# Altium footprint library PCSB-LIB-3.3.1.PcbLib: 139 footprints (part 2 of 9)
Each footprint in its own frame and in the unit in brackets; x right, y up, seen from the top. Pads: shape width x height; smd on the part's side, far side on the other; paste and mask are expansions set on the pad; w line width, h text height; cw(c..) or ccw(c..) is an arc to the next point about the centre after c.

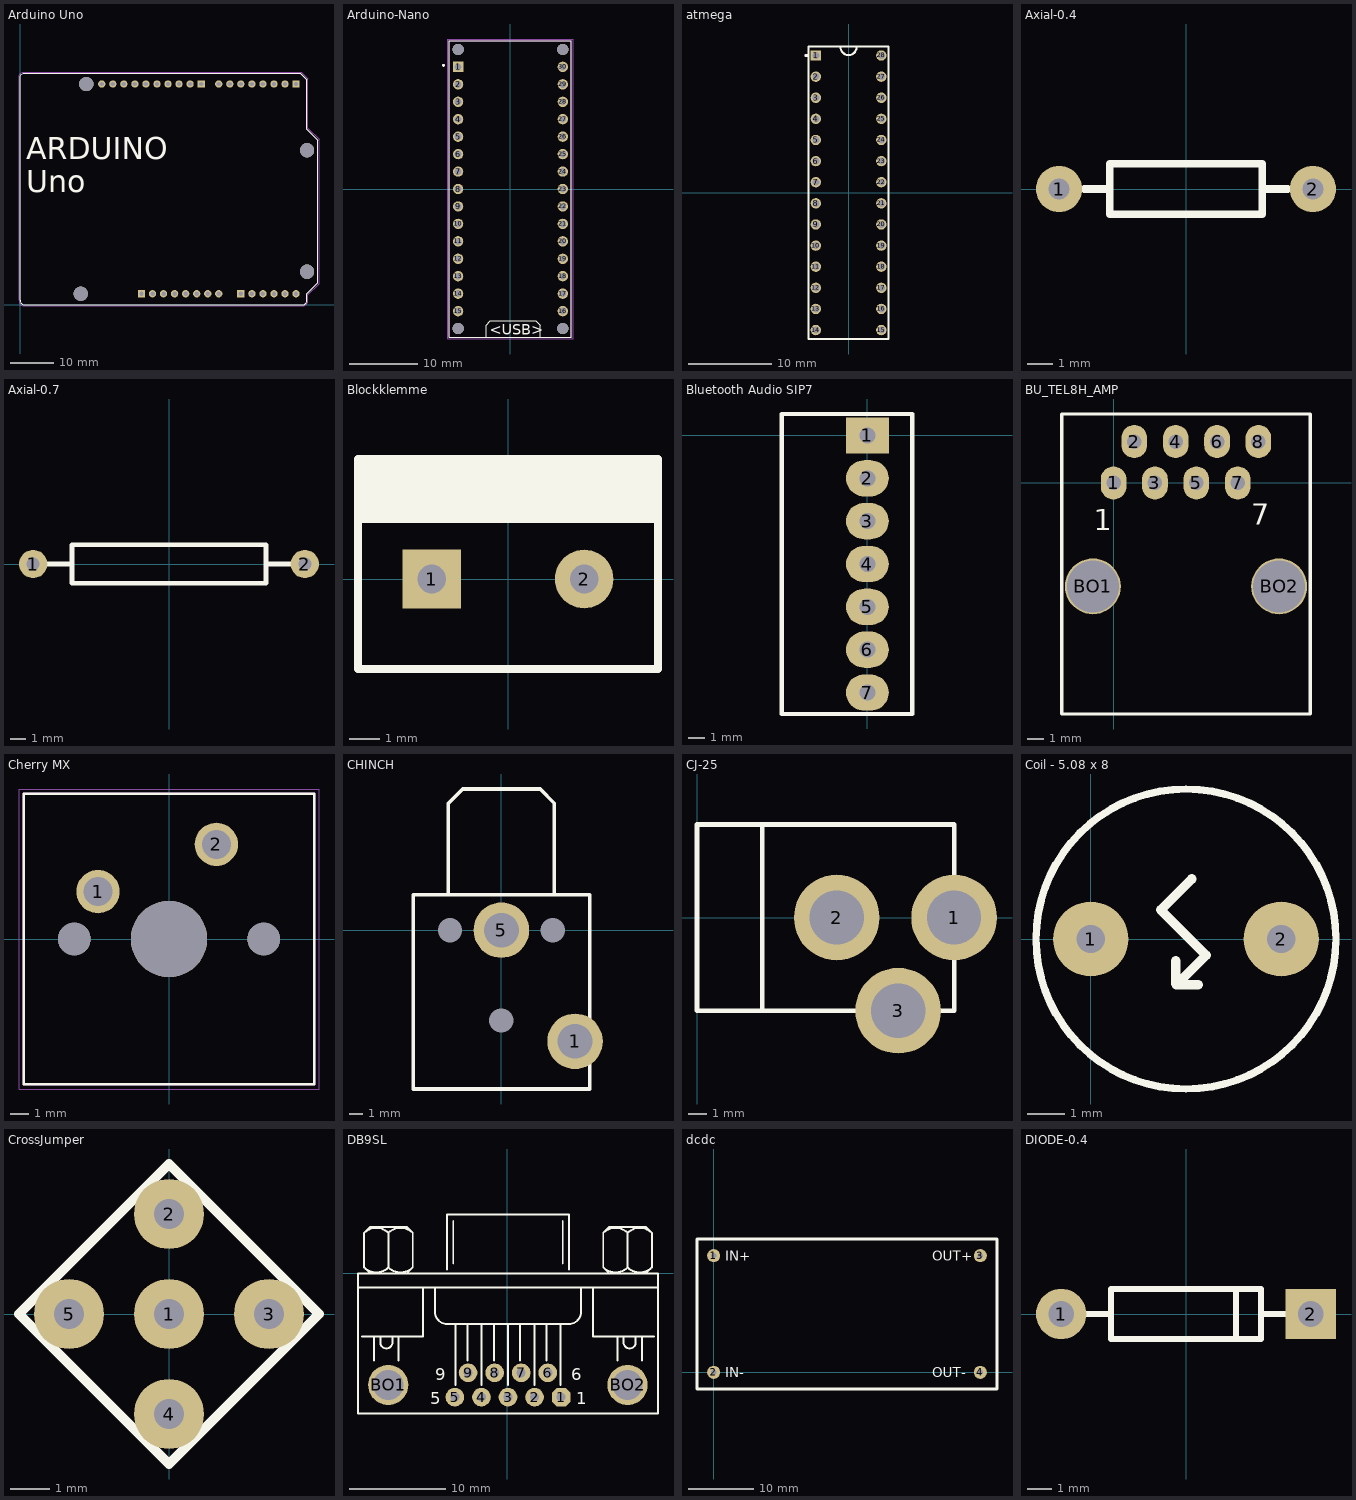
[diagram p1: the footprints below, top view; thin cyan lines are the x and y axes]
## Arduino Uno [mil]
pads (36):
  round 66 hole 40: 3V3(1400,100) 5V(1500,100) A1(2100,100) A2(2200,100) A3(2300,100) A4(2400,100) A4(SDA)(840,2000) A5(2500,100) A5(SCL)(740,2000) AREF(940,2000) D1(2400,2000) D2(2300,2000) D3(2200,2000) D4(2100,2000) D5(2000,2000) D6(1900,2000) D7(1800,2000) D9(1540,2000) D10(1440,2000) D11(1340,2000) D12(1240,2000) D13(1140,2000) GND_1(1700,100) GND_2(1600,100) GND_3(1040,2000) IOREF(1200,100) RST(1300,100) VIN(1800,100)
  rect 66x66 / inner round 66 / far side rect 66x66 hole 40: A0(2000,100) D0(2500,2000) D8(1640,2000) P1(1100,100)
  round 129.92 hole 129.92 unplated: ""(550,100) ""(600,2000) ""(2600,300) ""(2600,1400)
Top Overlay:
  lines w5: 0,39.1 1.67,29.1 5,19.94 11.66,11.61 19.99,4.94 29.16,1.61 39.15,-0.05 2559.09,-0.05 2569.09,1.61 2578.26,4.94 2586.59,11.61 2593.25,19.94 2596.58,29.1 2598.25,39.1 2598.25,99.91 2698.21,199.87 2698.21,1488.59 2598.25,1588.55 2598.25,2038.39 2538.27,2098.37 39.15,2098.37 29.16,2096.7 19.99,2092.54 11.66,2086.71 5,2078.38 1.67,2069.21 0,2058.39 0,39.1
  lines w10: 0,39.1 0,2058.39 1.67,2069.21 5,2078.38 11.66,2086.71 19.99,2092.54 29.16,2096.7 39.15,2098.37 2538.27,2098.37 2598.25,2038.39 2598.25,1588.55 2698.21,1488.59 2698.21,199.87 2598.25,99.91 2598.25,39.1 2596.58,29.1 2593.25,19.94 2586.59,11.61 2578.26,4.94 2569.09,1.61 2559.09,-0.05 39.15,-0.05 29.16,1.61 19.99,4.94 11.66,11.61 5,19.94 1.67,29.1 0,39.1
  text "ARDUINO  / Uno" at 55,1020.21 h200
Mechanical 15:
  lines w1.97: -9.84,39.1 -9.84,39.37 -9.84,2068.23 -8.18,2079.06 -4.84,2088.22 1.82,2096.55 10.15,2102.38 19.31,2106.55 29.31,2108.21 2548.11,2108.21 2608.09,2048.23 2608.09,1598.39 2708.06,1498.43 2708.06,190.03 2608.09,90.07 2608.09,39.1 ; -9.83,39.5 ccw(c36.7,36.25) 29.4,-9.82 ; 29.31,-9.9 2559.09,-9.9 ; 2558.61,-9.86 ccw(c2556.81,41.62) 2608.25,38.92

## Arduino-Nano [mm]
pads (34):
  rect 1.508x1.508 hole 1: 1(-7.62,17.78)
  round 1.508 hole 1: 2(-7.62,15.24) 3(-7.62,12.7) 4(-7.62,10.16) 5(-7.62,7.62) 6(-7.62,5.08) 7(-7.62,2.54) 8(-7.62,0) 9(-7.62,-2.54) 10(-7.62,-5.08) 11(-7.62,-7.62) 12(-7.62,-10.16) 13(-7.62,-12.7) 14(-7.62,-15.24) 15(-7.62,-17.78) 16(7.62,-17.78) 17(7.62,-15.24) 18(7.62,-12.7) 19(7.62,-10.16) 20(7.62,-7.62) 21(7.62,-5.08) 22(7.62,-2.54) 23(7.62,0) 24(7.62,2.54) 25(7.62,5.08) 26(7.62,7.62) 27(7.62,10.16) 28(7.62,12.7) 29(7.62,15.24) 30(7.62,17.78)
  round 1.651 hole 1.651 unplated: ""(-7.62,-20.32) ""(-7.62,20.32) ""(7.62,-20.32) ""(7.62,20.32)
Top Overlay:
  circle w0.2: c-9.75,18 r0.1
  lines w0.127: -3.556,-21.59 -3.556,-19.812 -2.921,-19.177 -2.159,-19.177 3.683,-19.177 4.318,-19.812 4.318,-21.59 ; -8.89,-21.59 8.89,-21.59 8.89,21.59 -8.89,21.59 -8.89,-21.59
  text "<USB>" at -3.048,-21.209 h1.52
Mechanical 13:
  circle w0.2: c-9.75,18 r0.1
  lines w0.127: -8.89,-21.59 -8.89,21.59 8.89,21.59 8.89,-21.59 -8.89,-21.59
Mechanical 15:
  lines w0.05: -9.14,-21.84 9.14,-21.84 9.14,21.84 -9.14,21.84 -9.14,-21.84

## atmega [mm]
pads (28):
  rect 1.25x1.25 hole 0.83: 1(-3.937,16.51)
  round 1.25 hole 0.83: 2(-3.937,13.97) 3(-3.937,11.43) 4(-3.937,8.89) 5(-3.937,6.35) 6(-3.937,3.81) 7(-3.937,1.27) 8(-3.937,-1.27) 9(-3.937,-3.81) 10(-3.937,-6.35) 11(-3.937,-8.89) 12(-3.937,-11.43) 13(-3.937,-13.97) 14(-3.937,-16.51) 15(3.937,-16.51) 16(3.937,-13.97) 17(3.937,-11.43) 18(3.937,-8.89) 19(3.937,-6.35) 20(3.937,-3.81) 21(3.937,-1.27) 22(3.937,1.27) 23(3.937,3.81) 24(3.937,6.35) 25(3.937,8.89) 26(3.937,11.43) 27(3.937,13.97) 28(3.937,16.51)
Top Overlay:
  circle w0.2: c-5.1,16.51 r0.1
  lines w0.254: -0.967,17.526 ccw(c0,17.526) 0.967,17.526 ; -4.812,-17.585 4.812,-17.585 4.812,17.585 -4.812,17.585 -4.812,-17.585
Mechanical 13:
  circle w0.2: c-5.1,16.51 r0.1

## Axial-0.4 [mm]
pads (2):
  round 1.85 hole 0.85: 1(-5.08,0) 2(5.08,0)
Top Overlay:
  lines w0.305: -4.064,0 -3.048,0 ; 3.048,0 4.064,0 ; -3.048,-1.016 3.048,-1.016 3.048,1.016 -3.048,1.016 -3.048,-1.016

## Axial-0.7 [mm]
pads (2):
  round 1.85 hole 0.85: 1(-8.89,0) 2(8.89,0)
Top Overlay:
  lines w0.305: -8.89,0 -6.35,0 ; 6.35,0 8.89,0 ; -6.35,-1.27 6.35,-1.27 6.35,1.27 -6.35,1.27 -6.35,-1.27

## Blockklemme [mm]
pads (2):
  rect 1.95x1.95 hole 0.95: 1(-2.54,0)
  round 1.95 hole 0.95: 2(2.54,0)
Top Overlay:
  rectangle: -5,2 5,4
  lines w0.254: -5,2 5,2 ; -5,-3 -5,3 -5,4 5,4 5,3 5,-3 -5,-3

## Bluetooth Audio SIP7 [mm]
pads (7):
  rect 2.54x2.15 / inner rect 2.54x1.27 / far side rect 2.54x2.15 hole 0.95: 1(0,0)
  oval 2.54x2.15 / inner oval 2.54x1.27 / far side oval 2.54x2.15 hole 0.95: 2(0,-2.54) 3(0,-5.08) 4(0,-7.62) 5(0,-10.16) 6(0,-12.7) 7(0,-15.24)
Top Overlay:
  lines w0.254: -5.08,-16.51 -5.08,1.27 2.667,1.27 2.667,-16.51 -5.08,-16.51

## BU_TEL8H_AMP [mil]
pads (10):
  oval 62x80 hole 35: 1(0,0) 2(50,100) 3(100,0) 4(150,100) 5(200,0) 6(250,100) 7(300,0) 8(350,100)
  round 135 hole 125: BO1(-50,-250) BO2(400,-250)
Bottom Layer:
  text "1" at -140,-15 h40
Top Overlay:
  lines w8: -125,-558.33 475,-558.33 475,166.67 -125,166.67 -125,-558.33
  text "7" at 332.45,-101.06 h50
  text "1" at -47.84,-114.13 h50

## Cherry MX [mil]
pads (5):
  round 91.5 hole 61: 1(-150,100) 2(100,200)
  round 69 hole 69 unplated: ""(-200,0) ""(200,0)
  round 161 hole 161 unplated: ""(0,0)
Top Overlay:
  lines w5: -307.09,-307.09 307.09,-307.09 307.09,307.09 -307.09,307.09 -307.09,-307.09
Mechanical 13:
  lines w5: -307.09,-307.09 -307.09,307.09 307.09,307.09 307.09,-307.09 -307.09,-307.09
Mechanical 15:
  lines w1.97: -316.93,-316.93 -316.93,316.93 316.93,316.93 316.93,-316.93 -316.93,-316.93

## CHINCH [mm] "RCA-Buchse bestellbar bei RS  Nr. 913-1021"
pads (5):
  round 4 / inner round 1.27 / far side round 4 hole 2.5: 1(5.3,-8) 5(0,0)
  round 0.5 hole 1.75: 2(3.7,0) 3(-3.7,0) 4(0,-6.5)
Top Overlay:
  lines w0.254: -3.81,2.54 -3.81,9.144 -2.794,10.16 2.794,10.16 3.81,9.144 3.81,2.54 ; -6.35,-11.43 6.35,-11.43 6.35,2.54 5.08,2.54 -5.08,2.54 -6.35,2.54 -6.35,-11.43

## CJ-25 [mm] "DC-Buchse 2.1mm Bestellbar bei RS Nr. 448-382"
height 1.7
pads (3):
  round 4.6 hole 2.9: 1(13.8,0) 2(7.5,0) 3(10.8,-5)
Top Overlay:
  lines w0.254: 3.5,-5 3.5,5 ; 0,-5 13.8,-5 13.8,5 0,5 0,-5

## Coil - 5.08 x 8 [mm]
pads (2):
  round 2 hole 0.75: 1(0,0) 2(5.08,0)
Top Overlay:
  circle w0.2: c2.54,0 r4
  lines w0.254: 2.261,-0.762 2.261,-1.194 ; 2.261,-0.584 2.261,-1.194 ; 2.692,1.6 1.867,0.775 3.073,-0.432 2.286,-1.219 ; 2.261,-1.194 2.286,-1.219 ; 2.286,-1.219 2.87,-1.219 ; 2.286,-1.219 2.87,-1.219 ; 2.286,-1.219 2.87,-1.219

## CrossJumper [mil]
pads (5):
  round 70 hole 30: 1(0,0) 2(0,100) 3(100,0) 4(0,-100) 5(-100,0)
Top Overlay:
  lines w10: -150,0 0,-150 150,0 0,150 -150,0

## DB9SL [mm]
pads (11):
  oct 1.95x1.95 hole 0.95: 1(5.6,-12.937)
  round 1.95 hole 0.95: 2(2.827,-12.937) 3(0.054,-12.937) 4(-2.718,-12.937) 5(-5.491,-12.937) 6(4.203,-10.397) 7(1.43,-10.397) 8(-1.343,-10.397) 9(-4.115,-10.397)
  round 4.2 hole 3.15: BO1(-12.455,-11.667) BO2(12.543,-11.667)
Top Overlay:
  lines w0.203: -15.609,-1.507 15.718,-1.507 ; -15.186,-6.587 -8.836,-6.587 -8.836,-1.507 ; -14.976,0.608 ccw(c-13.704,1.88) -12.432,0.608 ; -14.976,4.211 cw(c-13.704,2.938) -12.432,4.211 ; -14.339,-0.025 -14.974,0.61 -14.974,4.208 -14.339,4.843 -10.529,4.843 -9.894,4.208 -9.894,0.61 -10.529,-0.025 ; -13.916,-9.127 -13.916,-6.587 ; -13.281,-6.587 -13.281,-7.222 ccw(c-12.646,-7.222) -12.011,-7.222 -12.011,-6.587 ; -12.436,0.608 ccw(c-11.164,1.88) -9.892,0.608 ; -12.436,4.211 cw(c-11.164,2.938) -9.892,4.211 ; -12.434,0.61 -12.434,4.208 ; -11.376,-9.127 -11.376,-6.587 ; -7.566,-1.507 -7.566,-4.047 ccw(c-6.296,-4.047) -6.296,-5.317 6.404,-5.317 ccw(c6.404,-4.047) 7.674,-4.047 7.674,-1.507 ; -6.296,0.398 -6.296,6.113 6.404,6.113 6.404,0.398 ; -5.661,1.033 -5.661,5.478 ; -5.449,-11.667 -5.449,-5.317 ; -4.179,-9.127 -4.179,-5.317 ; -2.697,-11.667 -2.697,-5.317 ; -1.427,-9.127 -1.427,-5.317 ; 0.054,-11.667 0.054,-5.317 ; 1.324,-9.127 1.324,-5.317 ; 2.806,-11.667 2.806,-5.317 ; 4.076,-9.127 4.076,-8.915 4.076,-5.317 ; 5.558,-11.667 5.558,-5.317 ; 5.769,1.033 5.769,5.478 ; 8.944,-1.507 8.944,-6.587 15.294,-6.587 ; 10,0.608 ccw(c11.273,1.88) 12.545,0.608 ; 10,4.211 cw(c11.273,2.938) 12.545,4.211 ; 10.638,-0.025 10.003,0.61 10.003,4.208 10.638,4.843 14.448,4.843 15.083,4.208 15.083,0.61 14.448,-0.025 ; 11.484,-9.127 11.484,-6.587 ; 12.119,-6.587 12.119,-7.222 ccw(c12.754,-7.222) 13.389,-7.222 13.389,-6.587 ; 12.54,0.608 ccw(c13.813,1.88) 15.085,0.608 ; 12.54,4.211 cw(c13.813,2.938) 15.085,4.211 ; 12.543,0.61 12.543,4.208 ; 14.024,-9.127 14.024,-6.587 ; -15.609,-14.63 15.718,-14.63 15.718,-0.025 -15.609,-0.025 -15.609,-14.63
  text "6" at 6.658,-11.159 h1.27
  text "1" at 7.166,-13.699 h1.27
  text "5" at -8.074,-13.699 h1.27
  text "9" at -7.566,-11.159 h1.27

## dcdc [mm]
pads (4):
  round 2 hole 0.85: 1(0,17.78) 2(0,0) 3(40.64,17.78) 4(40.64,0)
Top Overlay:
  lines w0.4: -2.54,-2.54 -2.54,20.32 43.18,20.32 43.18,-2.54 -2.54,-2.54
  text "IN+" at 1.778,17.018 h1.52
  text "IN-" at 1.778,-0.762 h1.52
  text "OUT+" at 33.274,17.018 h1.52
  text "OUT-" at 33.274,-0.762 h1.52

## DIODE-0.4 [mm]
pads (2):
  round 2.05 hole 1.05: 1(-5.08,0)
  rect 2.05x2.05 hole 1.05: 2(5.08,0)
Top Overlay:
  lines w0.254: -4.064,0 -3.048,0 ; 2.032,-1.016 2.032,1.016 ; 3.048,0 4.064,0 ; -3.048,-1.016 3.048,-1.016 3.048,1.016 -3.048,1.016 -3.048,-1.016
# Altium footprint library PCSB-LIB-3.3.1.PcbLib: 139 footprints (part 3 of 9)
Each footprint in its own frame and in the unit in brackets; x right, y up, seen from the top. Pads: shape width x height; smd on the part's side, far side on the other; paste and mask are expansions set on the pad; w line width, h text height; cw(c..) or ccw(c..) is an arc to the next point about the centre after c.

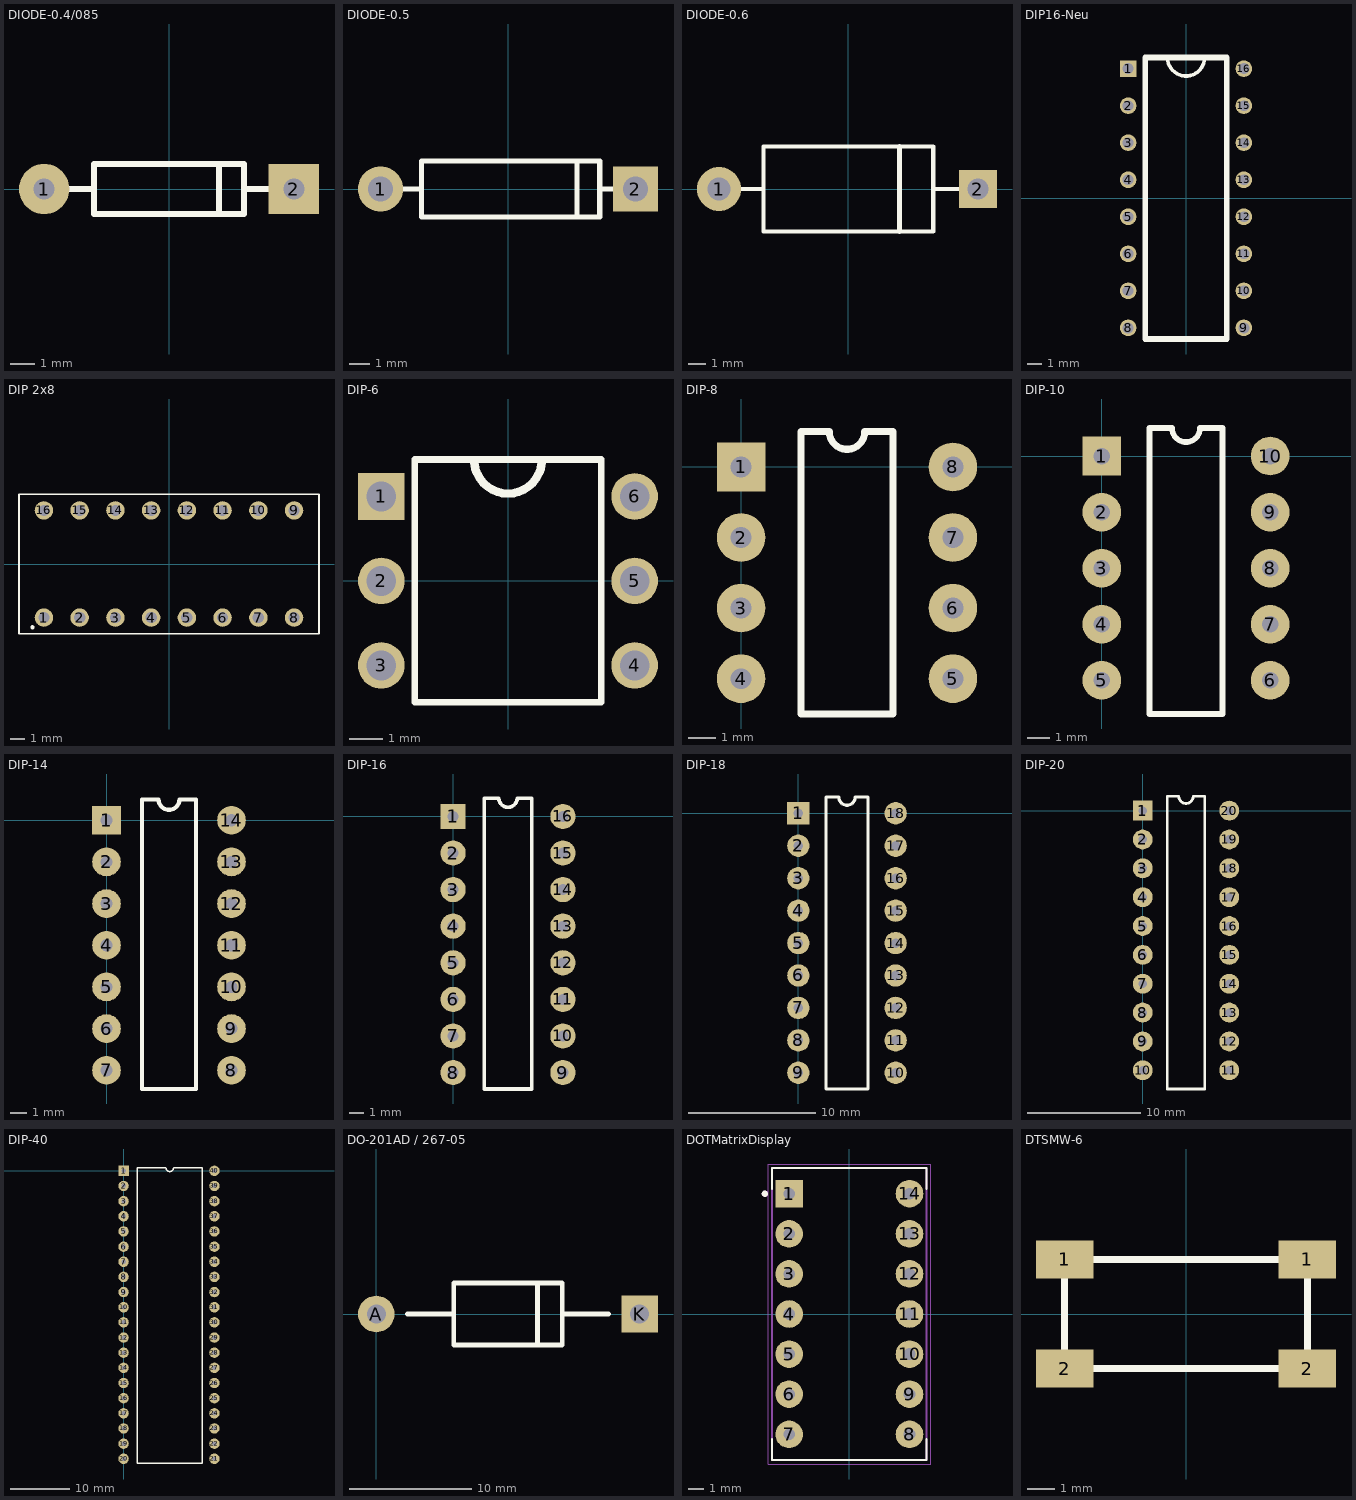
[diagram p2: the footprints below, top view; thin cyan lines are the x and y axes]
## DIODE-0.4/085 [mm]
pads (2):
  round 2.05 hole 0.85: 1(-5.08,0)
  rect 2.05x2.05 hole 0.85: 2(5.08,0)
Top Overlay:
  lines w0.254: -4.064,0 -3.048,0 ; 2.032,-1.016 2.032,1.016 ; 3.048,0 4.064,0 ; -3.048,-1.016 3.048,-1.016 3.048,1.016 -3.048,1.016 -3.048,-1.016

## DIODE-0.5 [mm]
pads (2):
  round 2.25 hole 1.25: 1(-6.35,0)
  rect 2.25x2.25 hole 1.25: 2(6.35,0)
Top Overlay:
  lines w0.254: -5.334,0 -4.318,0 ; 3.429,-1.397 3.429,1.397 ; 4.699,0 5.715,0 ; -4.318,-1.397 -4.318,1.397 4.572,1.397 4.572,-1.397 -4.318,-1.397

## DIODE-0.6 [mm]
pads (2):
  round 2.6 hole 1.35: 1(-7.62,0)
  rect 2.25x2.25 hole 1.25: 2(7.62,0)
Top Overlay:
  lines w0.254: -7,0 -5,0 ; -5,-2.5 -5,2.5 5,2.5 5,-2.5 -4.89,-2.5 ; 5,0 7.016,0
  lines w0.3: 3,-2.5 3,2.5

## DIP16-Neu [mm]
pads (16):
  rect 1.14x1.14 hole 0.74: 1(-3.97,8.89)
  round 1.14 hole 0.74: 2(-3.97,6.35) 3(-3.97,3.81) 4(-3.97,1.27) 5(-3.97,-1.27) 6(-3.97,-3.81) 7(-3.97,-6.35) 8(-3.97,-8.89) 9(3.97,-8.89) 10(3.97,-6.35) 11(3.97,-3.81) 12(3.97,-1.27) 13(3.97,1.27) 14(3.97,3.81) 15(3.97,6.35) 16(3.97,8.89)
Top Overlay:
  lines w0.254: -1.253,9.443 ccw(c0,9.653) 1.27,9.652
  lines w0.4: -2.794,-9.653 -2.794,9.653 2.794,9.653 2.794,-9.653 -2.794,-9.653

## DIP 2x8 [mm]
pads (16):
  round 1.308 hole 0.8: 1(-8.89,-3.81) 2(-6.35,-3.81) 3(-3.81,-3.81) 4(-1.27,-3.81) 5(1.27,-3.81) 6(3.81,-3.81) 7(6.35,-3.81) 8(8.89,-3.81) 9(8.89,3.81) 10(6.35,3.81) 11(3.81,3.81) 12(1.27,3.81) 13(-1.27,3.81) 14(-3.81,3.81) 15(-6.35,3.81) 16(-8.89,3.81)
Top Overlay:
  circle w0.2: c-9.7,-4.5 r0.05
  lines w0.127: -10.66,-4.95 -10.66,4.95 10.66,4.95 10.66,-4.95 -10.66,-4.95

## DIP-6 [mm]
pads (6):
  rect 1.4x1.4 hole 0.9: 1(-3.81,2.54)
  round 1.4 hole 0.9: 2(-3.81,0) 3(-3.81,-2.54) 4(3.81,-2.54) 5(3.81,0) 6(3.81,2.54)
Top Overlay:
  lines w0.2: -2.8,-3.65 2.8,-3.65 2.8,3.65 1.4,3.65 -1.4,3.65 -2.8,3.65 -2.8,-3.65
  lines w0.254: -1.016,3.556 ccw(c0,3.65) 1.016,3.556

## DIP-8 [mm]
pads (8):
  rect 1.75x1.75 hole 0.75: 1(0,0)
  round 1.75 hole 0.75: 2(0,-2.54) 3(0,-5.08) 4(0,-7.62) 5(7.62,-7.62) 6(7.62,-5.08) 7(7.62,-2.54) 8(7.62,0)
Top Overlay:
  lines w0.254: 2.159,-8.89 5.461,-8.89 5.461,1.27 4.445,1.27 cw(c3.81,1.27) 3.175,1.27 2.159,1.27 2.159,-8.89

## DIP-10 [mm]
pads (10):
  rect 1.75x1.75 hole 0.75: 1(0,0)
  round 1.75 hole 0.75: 2(0,-2.54) 3(0,-5.08) 4(0,-7.62) 5(0,-10.16) 6(7.62,-10.16) 7(7.62,-7.62) 8(7.62,-5.08) 9(7.62,-2.54) 10(7.62,0)
Top Overlay:
  lines w0.254: 2.159,-11.684 2.159,1.27 3.175,1.27 ccw(c3.81,1.27) 4.445,1.27 5.461,1.27 5.461,-11.684 2.159,-11.684

## DIP-14 [mm]
pads (14):
  rect 1.75x1.75 hole 0.75: 1(0,0)
  round 1.75 hole 0.75: 2(0,-2.54) 3(0,-5.08) 4(0,-7.62) 5(0,-10.16) 6(0,-12.7) 7(0,-15.24) 8(7.62,-15.24) 9(7.62,-12.7) 10(7.62,-10.16) 11(7.62,-7.62) 12(7.62,-5.08) 13(7.62,-2.54) 14(7.62,0)
Top Overlay:
  lines w0.254: 2.159,-16.383 2.159,1.27 3.175,1.27 ccw(c3.81,1.27) 4.445,1.27 5.461,1.27 5.461,-16.383 2.159,-16.383

## DIP-16 [mm]
pads (16):
  rect 1.75x1.75 hole 0.75: 1(0,0)
  round 1.75 hole 0.75: 2(0,-2.54) 3(0,-5.08) 4(0,-7.62) 5(0,-10.16) 6(0,-12.7) 7(0,-15.24) 8(0,-17.78) 9(7.62,-17.78) 10(7.62,-15.24) 11(7.62,-12.7) 12(7.62,-10.16) 13(7.62,-7.62) 14(7.62,-5.08) 15(7.62,-2.54) 16(7.62,0)
Top Overlay:
  lines w0.254: 2.159,-18.923 5.461,-18.923 5.461,1.27 4.445,1.27 cw(c3.81,1.27) 3.175,1.27 2.159,1.27 2.159,-18.923

## DIP-18 [mm]
pads (18):
  rect 1.75x1.75 hole 0.75: 1(0,0)
  round 1.75 hole 0.75: 2(0,-2.54) 3(0,-5.08) 4(0,-7.62) 5(0,-10.16) 6(0,-12.7) 7(0,-15.24) 8(0,-17.78) 9(0,-20.32) 10(7.62,-20.32) 11(7.62,-17.78) 12(7.62,-15.24) 13(7.62,-12.7) 14(7.62,-10.16) 15(7.62,-7.62) 16(7.62,-5.08) 17(7.62,-2.54) 18(7.62,0)
Top Overlay:
  lines w0.254: 2.159,-21.59 2.159,1.27 3.175,1.27 ccw(c3.81,1.27) 4.445,1.27 5.461,1.27 5.461,-21.59 2.159,-21.59

## DIP-20 [mm]
pads (20):
  rect 1.75x1.75 hole 0.75: 1(0,0)
  round 1.75 hole 0.75: 2(0,-2.54) 3(0,-5.08) 4(0,-7.62) 5(0,-10.16) 6(0,-12.7) 7(0,-15.24) 8(0,-17.78) 9(0,-20.32) 10(0,-22.86) 11(7.62,-22.86) 12(7.62,-20.32) 13(7.62,-17.78) 14(7.62,-15.24) 15(7.62,-12.7) 16(7.62,-10.16) 17(7.62,-7.62) 18(7.62,-5.08) 19(7.62,-2.54) 20(7.62,0)
Top Overlay:
  lines w0.254: 2.159,-24.511 2.159,1.27 3.175,1.27 ccw(c3.81,1.27) 4.445,1.27 5.461,1.27 5.461,-24.511 2.159,-24.511

## DIP-40 [mm]
pads (40):
  rect 1.75x1.75 hole 0.75: 1(0,0)
  round 1.75 hole 0.75: 2(0,-2.54) 3(0,-5.08) 4(0,-7.62) 5(0,-10.16) 6(0,-12.7) 7(0,-15.24) 8(0,-17.78) 9(0,-20.32) 10(0,-22.86) 11(0,-25.4) 12(0,-27.94) 13(0,-30.48) 14(0,-33.02) 15(0,-35.56) 16(0,-38.1) 17(0,-40.64) 18(0,-43.18) 19(0,-45.72) 20(0,-48.26) 21(15.24,-48.26) 22(15.24,-45.72) 23(15.24,-43.18) 24(15.24,-40.64) 25(15.24,-38.1) 26(15.24,-35.56) 27(15.24,-33.02) 28(15.24,-30.48) 29(15.24,-27.94) 30(15.24,-25.4) 31(15.24,-22.86) 32(15.24,-20.32) 33(15.24,-17.78) 34(15.24,-15.24) 35(15.24,-12.7) 36(15.24,-10.16) 37(15.24,-7.62) 38(15.24,-5.08) 39(15.24,-2.54) 40(15.24,0)
Top Overlay:
  lines w0.254: 2.286,-49.022 13.208,-49.022 13.208,0.508 8.382,0.508 cw(c7.747,0.508) 7.112,0.508 2.286,0.508 2.286,-49.022

## DO-201AD / 267-05 [mm]
height 5
pads (2):
  round 3 hole 1.55: A(0,0)
  rect 3x3 hole 1.55: K(21.59,0)
Top Overlay:
  lines w0.4: 2.54,0 6.35,0 ; 13.208,-2.54 13.208,2.54 ; 15.24,0 19.05,0 ; 6.35,-2.54 6.35,2.54 15.24,2.54 15.24,-2.54 6.35,-2.54

## DOTMatrixDisplay [mm]
pads (14):
  rect 1.75x1.75 hole 0.75: 1(-3.81,7.62)
  round 1.75 hole 0.75: 2(-3.81,5.08) 3(-3.81,2.54) 4(-3.81,0) 5(-3.81,-2.54) 6(-3.81,-5.08) 7(-3.81,-7.62) 8(3.81,-7.62) 9(3.81,-5.08) 10(3.81,-2.54) 11(3.81,0) 12(3.81,2.54) 13(3.81,5.08) 14(3.81,7.62)
Top Overlay:
  circle w0.2: c-5.35,7.62 r0.1
  lines w0.127: -4.9,-7.92 -4.9,-9.25 4.9,-9.25 4.9,-7.92 ; -4.9,7.92 -4.9,9.25 4.9,9.25 4.9,7.92
Mechanical 13:
  circle w0.2: c-5.35,7.62 r0.1
  lines w0.127: -4.9,-9.25 -4.9,9.25 4.9,9.25 4.9,-9.25 -4.9,-9.25
Mechanical 15:
  lines w0.05: -5.15,-9.5 5.15,-9.5 5.15,9.5 -5.15,9.5 -5.15,-9.5

## DTSMW-6 [mm]
height 17
pads (4):
  rect 2.1x1.4 smd: 1(-4.45,2) 1(4.45,2) 2(-4.45,-2) 2(4.45,-2)
Top Overlay:
  lines w0.254: -4.45,-2 -4.45,2 4.45,2 4.45,-2 -4.45,-2
3D body: height 17, standoff 0, extent -5.602,-2.802 5.602,2.802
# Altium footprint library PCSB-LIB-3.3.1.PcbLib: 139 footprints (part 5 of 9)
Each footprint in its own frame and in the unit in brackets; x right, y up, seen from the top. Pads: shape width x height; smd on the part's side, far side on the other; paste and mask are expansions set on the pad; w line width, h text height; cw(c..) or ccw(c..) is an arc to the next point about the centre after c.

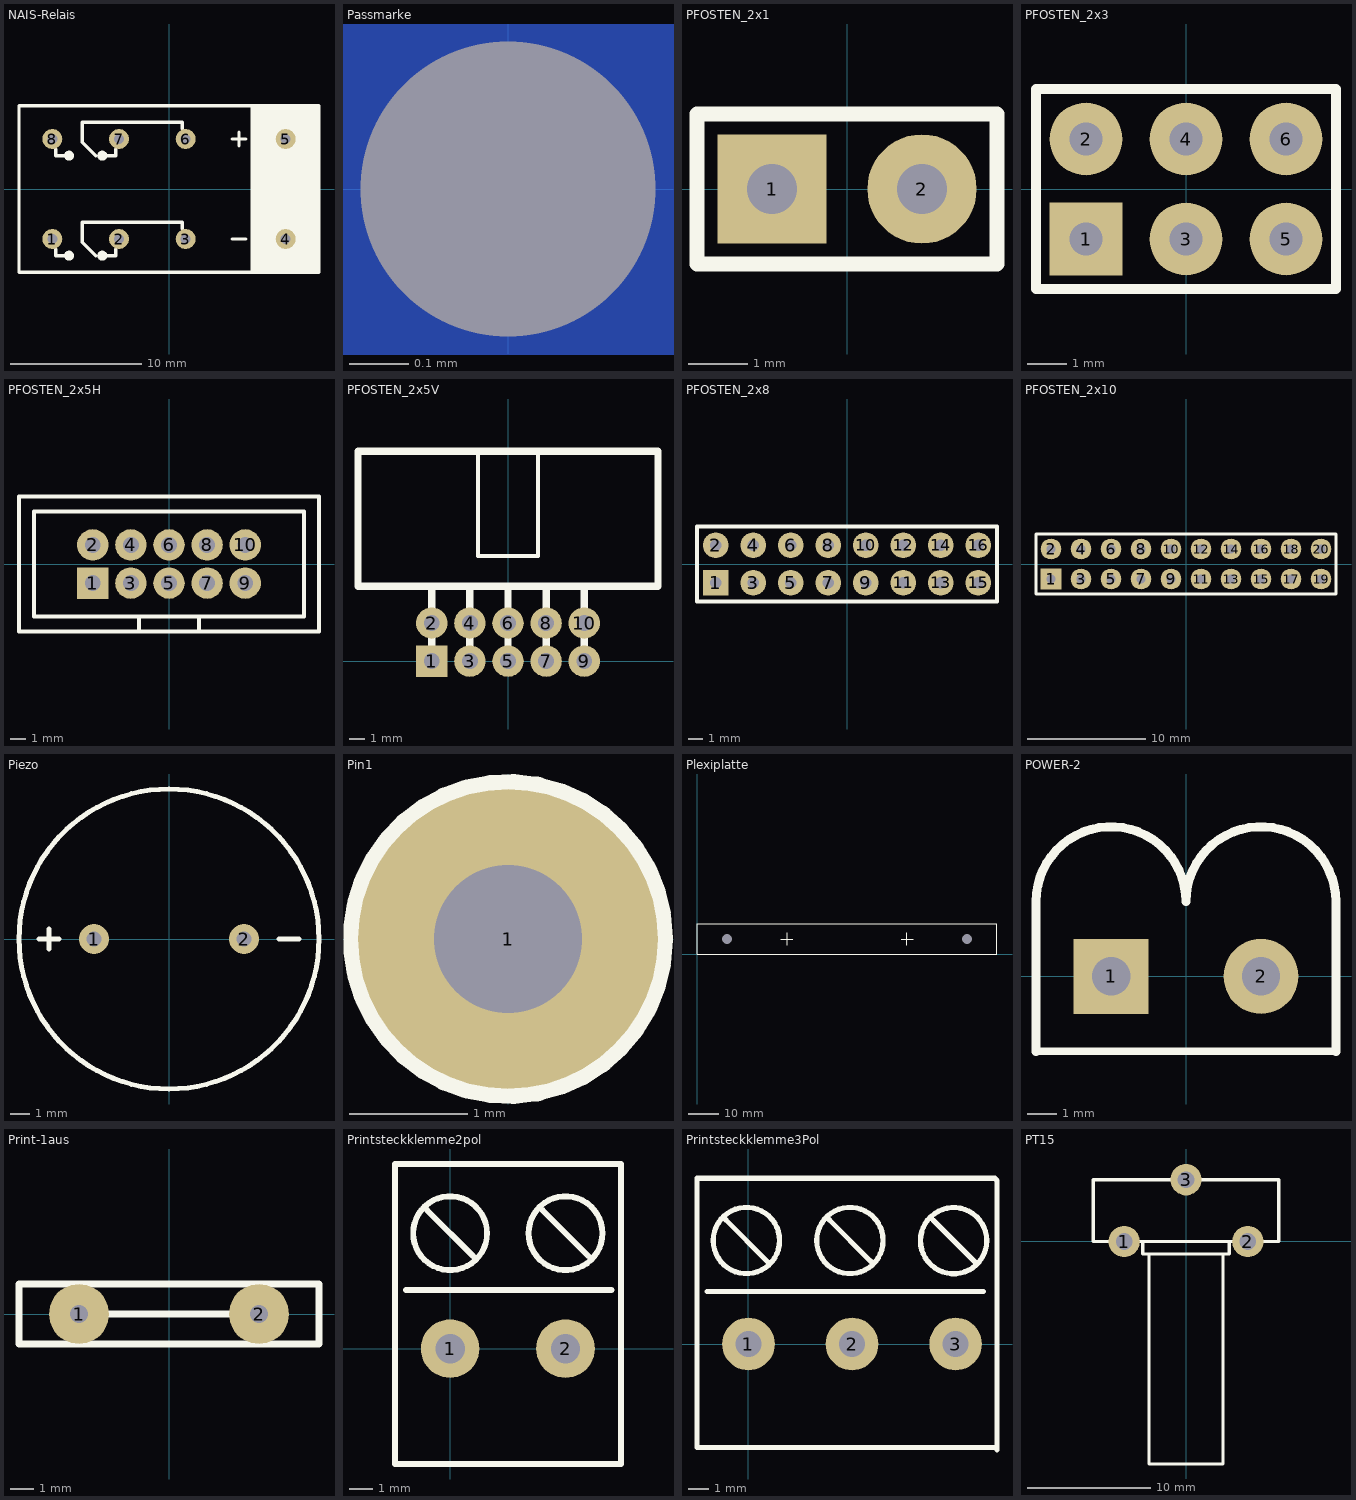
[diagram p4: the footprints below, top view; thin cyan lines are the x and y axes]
## NAIS-Relais [mil]
pads (8):
  round 60 hole 30: 1(-350,-150) 2(-150,-150) 3(50,-150) 4(350,-150) 5(350,150) 6(50,150) 7(-150,150) 8(-350,150)
Top Overlay:
  circle w10: c-300,-200 r10
  circle w10: c-200,-200 r10
  circle w10: c-300,100 r10
  circle w10: c-200,100 r10
  rectangle: 250,-250 450,250
  region: -310,-190 -290,-190 -290,-210 -310,-210
  region: -210,-190 -190,-190 -190,-210 -210,-210
  region: -206,109 -192,109 -192,93 -194,91 -207,91 -207,108
  region: -306,109 -305,108 -293,108 -293,94 -295,92 -302,92 -302,103 -307,108
  region: -290,100 -300,100 -299,99 -299,90 -300,90 -302,92 -300,94 -300,102 -295,97 -295,92
  lines w10: -340,-180 -340,-200 -300,-200 ; -340,120 -340,100 -300,100 ; -220,-200 -260,-160 -260,-120 -260,-100 40,-100 40,-120 ; -220,100 -260,140 -260,180 -260,200 40,200 40,180 ; -200,-200 -160,-200 -160,-180 ; -200,100 -160,100 -160,120 ; 190,-150 230,-150 ; 190,150 230,150 ; 210,130 210,170 ; 250,-250 250,250 ; -450,-250 450,-250 450,250 -450,250 -450,-250

## Passmarke [mm]
pads (1):
  round 0 hole 0.5 unplated: 0(0,0)
Bottom Layer:
  circle w0.5: c0,0 r0.25

## PFOSTEN_2x1 [mm]
pads (2):
  rect 1.85x1.85 hole 0.85 mask+0.102: 1(-1.27,0)
  round 1.85 hole 0.85 mask+0.102: 2(1.27,0)
Top Overlay:
  lines w0.254: -2.54,-1.27 -2.54,1.27 2.54,1.27 2.54,-1.27 -2.54,-1.27

## PFOSTEN_2x3 [mm]
pads (6):
  rect 1.85x1.85 hole 0.85 mask+0.102: 1(-2.54,-1.27)
  round 1.85 hole 0.85 mask+0.102: 2(-2.54,1.27) 3(0,-1.27) 4(0,1.27) 5(2.54,-1.27) 6(2.54,1.27)
Top Overlay:
  lines w0.254: -3.81,-2.54 3.81,-2.54 3.81,2.54 -3.81,2.54 -3.81,-2.54

## PFOSTEN_2x5H [mm]
height 9
pads (10):
  rect 2.1x2.1 hole 1.05 mask+0.102: 1(-5.08,-1.27)
  round 2.1 hole 1.05 mask+0.102: 2(-5.08,1.27) 3(-2.54,-1.27) 4(-2.54,1.27) 5(0,-1.27) 6(0,1.27) 7(2.54,-1.27) 8(2.54,1.27) 9(5.08,-1.27) 10(5.08,1.27)
Top Overlay:
  lines w0.254: -2,-4.5 -2,-3.5 ; -0.5,4.5 10,4.5 10,-4.5 -10,-4.5 -10,4.5 0,4.5 ; 2,-4.5 2,-3.5 ; -9,-3.5 -9,3.5 9,3.5 9,-3.5 -9,-3.5

## PFOSTEN_2x5V [mm]
height 9
pads (10):
  rect 2.1x2.1 hole 1.05 mask+0.102: 1(-5.08,0)
  round 2.1 hole 1.05 mask+0.102: 2(-5.08,2.54) 3(-2.54,0) 4(-2.54,2.54) 5(0,0) 6(0,2.54) 7(2.54,0) 8(2.54,2.54) 9(5.08,0) 10(5.08,2.54)
Top Overlay:
  lines w0.254: -2,14 -2,7 2,7 2,14
  lines w0.5: -5.08,0 -5.08,5 ; -2.54,0 -2.54,5 ; 0,0 0,5 ; 2.54,0 2.54,5 ; 5.08,0 5.08,5 ; 0,5 10,5 10,14 -10,14 -10,5 0,5

## PFOSTEN_2x8 [mm]
pads (16):
  rect 1.75x1.75 hole 0.75: 1(-8.89,-1.27)
  round 1.75 hole 0.75: 2(-8.89,1.27) 3(-6.35,-1.27) 4(-6.35,1.27) 5(-3.81,-1.27) 6(-3.81,1.27) 7(-1.27,-1.27) 8(-1.27,1.27) 9(1.27,-1.27) 10(1.27,1.27) 11(3.81,-1.27) 12(3.81,1.27) 13(6.35,-1.27) 14(6.35,1.27) 15(8.89,-1.27) 16(8.89,1.27)
Top Overlay:
  lines w0.254: -10.16,-2.54 10.16,-2.54 10.16,2.54 -10.16,2.54 -10.16,-2.54

## PFOSTEN_2x10 [mm]
pads (20):
  rect 1.75x1.75 hole 0.75: 1(-11.43,-1.27)
  round 1.75 hole 0.75: 2(-11.43,1.27) 3(-8.89,-1.27) 4(-8.89,1.27) 5(-6.35,-1.27) 6(-6.35,1.27) 7(-3.81,-1.27) 8(-3.81,1.27) 9(-1.27,-1.27) 10(-1.27,1.27) 11(1.27,-1.27) 12(1.27,1.27) 13(3.81,-1.27) 14(3.81,1.27) 15(6.35,-1.27) 16(6.35,1.27) 17(8.89,-1.27) 18(8.89,1.27) 19(11.43,-1.27) 20(11.43,1.27)
Top Overlay:
  lines w0.254: -12.7,-2.54 12.7,-2.54 12.7,2.54 -12.7,2.54 -12.7,-2.54

## Piezo [mil]
pads (2):
  round 60 hole 30: 1(-150,0) 2(150,0)
Top Overlay:
  circle w10: c0,0 r300
  lines w10: -260,0 -220,0 ; -240,-20 -240,20 ; 220,0 260,0

## Pin1 [mm]
pads (1):
  round 2.54 hole 1.25: 1(0,0)
Top Overlay:
  circle w0.254: c0,0 r1.27

## Plexiplatte [mm]
height 60
pads (2):
  round 1.524 hole 3.2 unplated: 0(10,5) 0(90,5)
Top Overlay:
  lines w0.1: 28,5 32,5 ; 30,3 30,7 ; 68,5 72,5 ; 70,3 70,7
  lines w0.3: 0,0 100,0 100,10 0,10 0,0

## POWER-2 [mm]
pads (2):
  rect 2.54x2.54 hole 1.3: 1(-2.54,0)
  round 2.54 hole 1.3: 2(2.54,0)
Top Overlay:
  lines w0.254: -5.08,-2.54 5.08,-2.54
  lines w0.305: -5.08,-2.54 -5.085,2.531 cw(c-2.545,2.531) -0.005,2.531 cw(c2.535,2.531) 5.075,2.531 5.08,-2.54

## Print-1aus [mm]
height 8
pads (2):
  round 2.54 hole 0.75: 1(-3.81,0) 2(3.81,0)
Top Overlay:
  lines w0.3: -3.81,0 3.81,0 ; -6.35,-1.27 6.35,-1.27 6.35,1.27 0,1.27 -6.35,1.27 -6.35,-1.27

## Printsteckklemme2pol [mm] "Bestellbar bei RS Nr. 897-1297"
pads (2):
  round 2.54 hole 1.27: 1(0,0) 2(5,0)
Top Overlay:
  circle w0.254: c5,5 r1.601
  circle w0.254: c0,5 r1.601
  lines w0.1: 6,3.75 6,4
  lines w0.254: -1.905,2.54 6.985,2.54 ; -1,6 1,4 ; 4,6 6,4 ; 7.385,-5 -2.385,-5 -2.385,8 7.385,8 ; 7.4,-5 7.4,8

## Printsteckklemme3Pol [mm]
pads (3):
  round 2.54 hole 1.27: 1(0,0) 2(5,0) 3(10,0)
Top Overlay:
  circle w0.254: c9.907,4.993 r1.601
  circle w0.254: c4.9,5 r1.601
  circle w0.254: c-0.1,5 r1.601
  lines w0.1: 5.9,3.75 5.9,4 ; 10.907,3.743 10.907,3.993
  lines w0.254: -2.005,2.54 6.885,2.54 11.34,2.54 ; -1.1,6 0.9,4 ; 3.9,6 5.9,4 ; 8.907,5.993 10.907,3.993 ; 11.9,-5 7.285,-5 -2.485,-5 -2.485,8 7.285,8 11.9,8 12,7.9 12,-5.1

## PT15 [mm]
pads (3):
  round 2.54 hole 1.35: 1(-5.006,-0.011) 2(4.994,-0.011) 3(-0.006,4.989)
Top Overlay:
  lines w0.254: -3.506,-0.011 -3.506,-1.011 3.494,-1.011 3.494,-0.011 ; -3,-1.011 -3,-18 3,-18 3,-1.011 ; -7.506,-0.011 -7.506,4.989 7.494,4.989 7.494,-0.011 -7.506,-0.011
